(* Logix 5000 project; controller PDPMV1_120_v15 vendor 1 type 14 code 65 rev 15.1; software revision 15.00; part 2 of 3 *)
(* tags used below, declared in another part *)
   MVI69PDPMV1 : PDPMV1_ModuleDef;
(* MainProgram, continued *)

ROUTINE MainRoutine   (* ladder *)
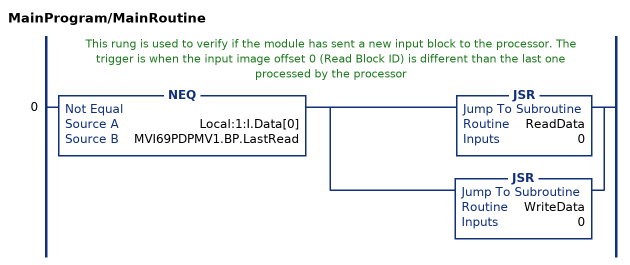
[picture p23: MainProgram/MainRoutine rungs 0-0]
   // This rung is used to verify if the module has sent a new input block to the processor. The trigger is when the input image offset 0 (Read Block ID) is different than the last one processed by the processor
   0: NEQ(Local:1:I.Data[0],MVI69PDPMV1.BP.LastRead)[JSR(ReadData,0) ,JSR(WriteData,0) ];
END_ROUTINE

ROUTINE ReadAlarm   (* ladder *)
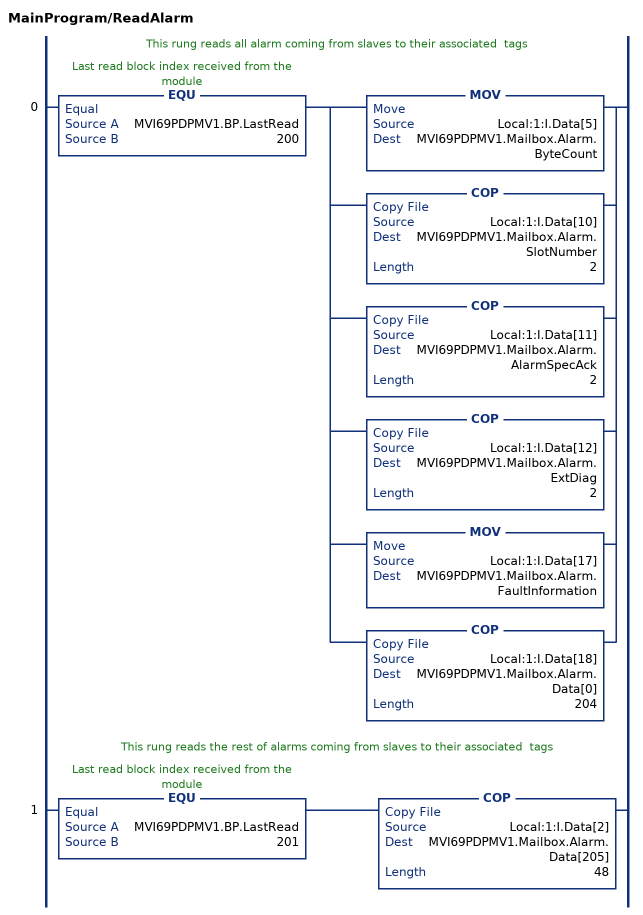
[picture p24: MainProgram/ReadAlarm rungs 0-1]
   // This rung reads all alarm coming from slaves to their associated  tags
   0: EQU(MVI69PDPMV1.BP.LastRead,200)[MOV(Local:1:I.Data[5],MVI69PDPMV1.Mailbox.Alarm.ByteCount) ,COP(Local:1:I.Data[10],MVI69PDPMV1.Mailbox.Alarm.SlotNumber,2) ,COP(Local:1:I.Data[11],MVI69PDPMV1.Mailbox.Alarm.AlarmSpecAck,2) ,COP(Local:1:I.Data[12],MVI69PDPMV1.Mailbox.Alarm.ExtDiag,2) ,MOV(Local:1:I.Data[17],MVI69PDPMV1.Mailbox.Alarm.FaultInformation) ,COP(Local:1:I.Data[18],MVI69PDPMV1.Mailbox.Alarm.Data[0],204) ];
   // This rung reads the rest of alarms coming from slaves to their associated  tags
   1: EQU(MVI69PDPMV1.BP.LastRead,201)COP(Local:1:I.Data[2],MVI69PDPMV1.Mailbox.Alarm.Data[205],48);
END_ROUTINE

ROUTINE ReadData   (* ladder *)
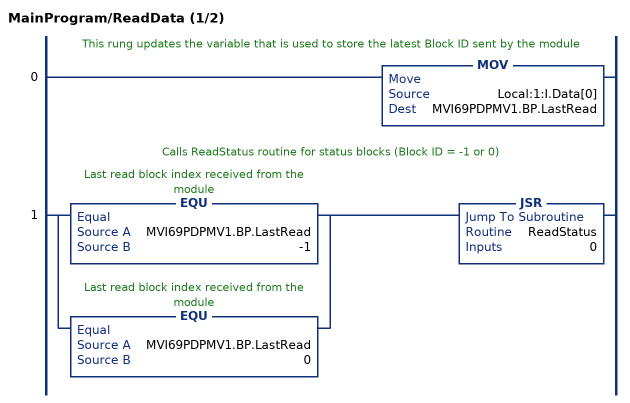
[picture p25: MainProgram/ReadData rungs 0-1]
   // This rung updates the variable that is used to store the latest Block ID sent by the module
   0: MOV(Local:1:I.Data[0],MVI69PDPMV1.BP.LastRead);
   // Calls ReadStatus routine for status blocks (Block ID = -1 or 0)
   1: [EQU(MVI69PDPMV1.BP.LastRead,-1) ,EQU(MVI69PDPMV1.BP.LastRead,0) ]JSR(ReadStatus,0);
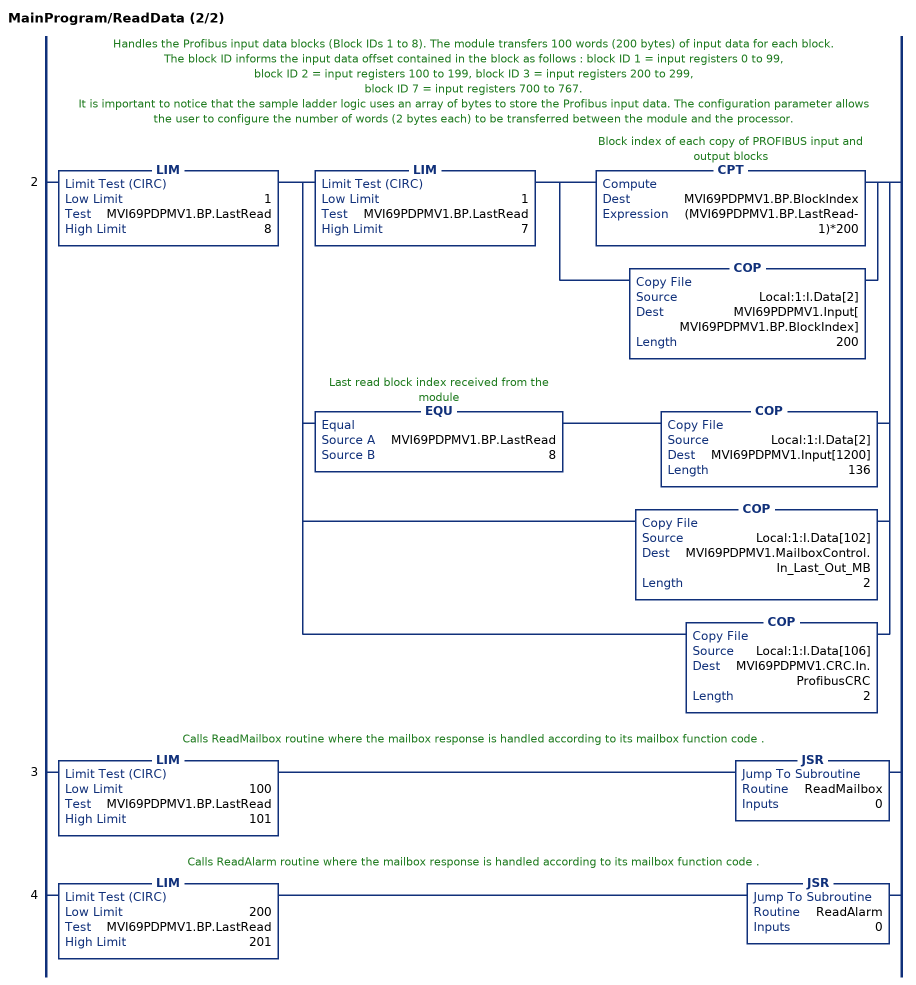
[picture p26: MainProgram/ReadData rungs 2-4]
   // Handles the Profibus input data blocks (Block IDs 1 to 8). The module transfers 100 words (200 bytes) of input data for each block.
   // The block ID informs the input data offset contained in the block as follows : block ID 1 = input registers 0 to 99,
   // block ID 2 = input registers 100 to 199, block ID 3 = input registers 200 to 299,
   // block ID 7 = input registers 700 to 767.
   // It is important to notice that the sample ladder logic uses an array of bytes to store the Profibus input data. The configuration parameter allows the user to configure the number of words (2 bytes each) to be transferred between the module and the processor.
   2: LIM(1,MVI69PDPMV1.BP.LastRead,8)[LIM(1,MVI69PDPMV1.BP.LastRead,7) [CPT(MVI69PDPMV1.BP.BlockIndex,(MVI69PDPMV1.BP.LastRead-1)*200) ,COP(Local:1:I.Data[2],MVI69PDPMV1.Input[MVI69PDPMV1.BP.BlockIndex],200) ] ,EQU(MVI69PDPMV1.BP.LastRead,8) COP(Local:1:I.Data[2],MVI69PDPMV1.Input[1200],136) ,COP(Local:1:I.Data[102],MVI69PDPMV1.MailboxControl.In_Last_Out_MB,2) ,COP(Local:1:I.Data[106],MVI69PDPMV1.CRC.In.ProfibusCRC,2) ];
   // Calls ReadMailbox routine where the mailbox response is handled according to its mailbox function code .
   3: LIM(100,MVI69PDPMV1.BP.LastRead,101)JSR(ReadMailbox,0);
   // Calls ReadAlarm routine where the mailbox response is handled according to its mailbox function code .
   4: LIM(200,MVI69PDPMV1.BP.LastRead,201)JSR(ReadAlarm,0);
END_ROUTINE

ROUTINE ReadMailbox   (* ladder *)
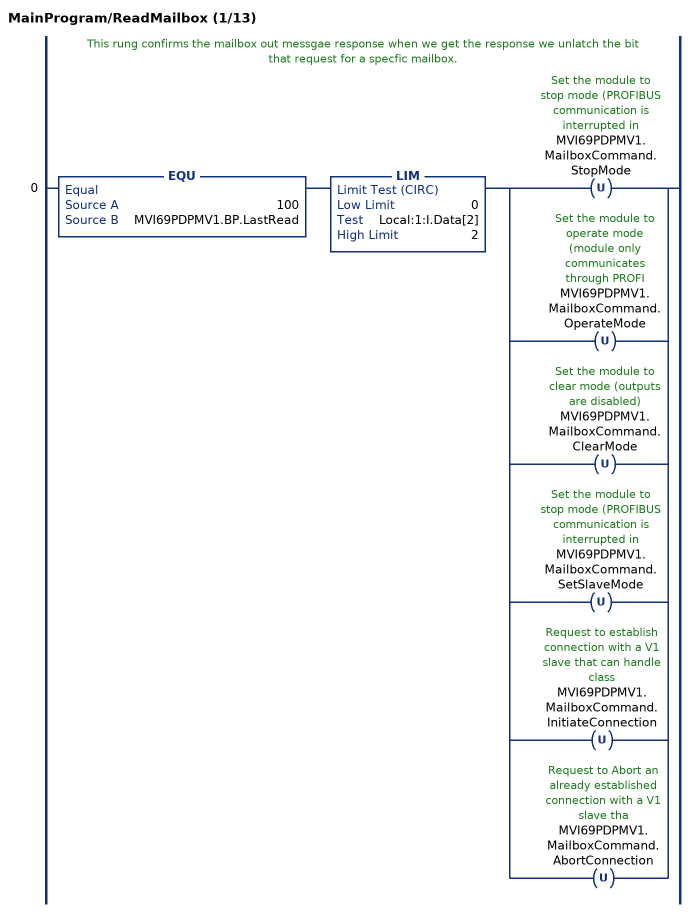
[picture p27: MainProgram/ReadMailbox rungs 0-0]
   // This rung confirms the mailbox out messgae response when we get the response we unlatch the bit that request for a specfic mailbox.
   0: EQU(100,MVI69PDPMV1.BP.LastRead)LIM(0,Local:1:I.Data[2],2)[OTU(MVI69PDPMV1.MailboxCommand.StopMode) ,OTU(MVI69PDPMV1.MailboxCommand.OperateMode) ,OTU(MVI69PDPMV1.MailboxCommand.ClearMode) ,OTU(MVI69PDPMV1.MailboxCommand.SetSlaveMode) ,OTU(MVI69PDPMV1.MailboxCommand.InitiateConnection) ,OTU(MVI69PDPMV1.MailboxCommand.AbortConnection) ];
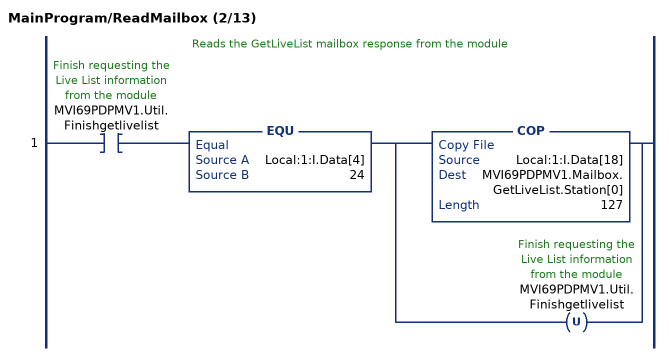
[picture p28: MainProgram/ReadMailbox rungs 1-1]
   // Reads the GetLiveList mailbox response from the module
   1: XIC(MVI69PDPMV1.Util.Finishgetlivelist)EQU(Local:1:I.Data[4],24)[COP(Local:1:I.Data[18],MVI69PDPMV1.Mailbox.GetLiveList.Station[0],127) ,OTU(MVI69PDPMV1.Util.Finishgetlivelist) ];
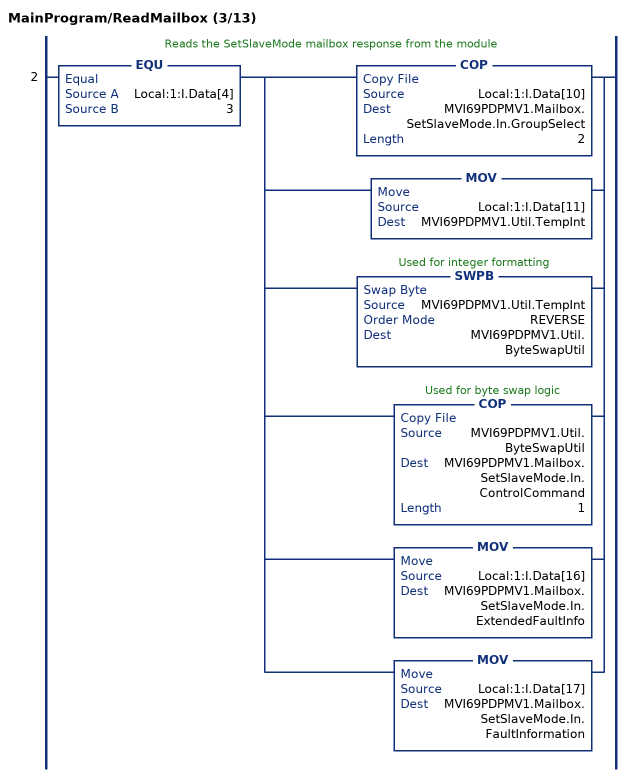
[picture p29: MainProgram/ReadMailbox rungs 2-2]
   // Reads the SetSlaveMode mailbox response from the module
   2: EQU(Local:1:I.Data[4],3)[COP(Local:1:I.Data[10],MVI69PDPMV1.Mailbox.SetSlaveMode.In.GroupSelect,2) ,MOV(Local:1:I.Data[11],MVI69PDPMV1.Util.TempInt) ,SWPB(MVI69PDPMV1.Util.TempInt,REVERSE,MVI69PDPMV1.Util.ByteSwapUtil) ,COP(MVI69PDPMV1.Util.ByteSwapUtil,MVI69PDPMV1.Mailbox.SetSlaveMode.In.ControlCommand,1) ,MOV(Local:1:I.Data[16],MVI69PDPMV1.Mailbox.SetSlaveMode.In.ExtendedFaultInfo) ,MOV(Local:1:I.Data[17],MVI69PDPMV1.Mailbox.SetSlaveMode.In.FaultInformation) ];
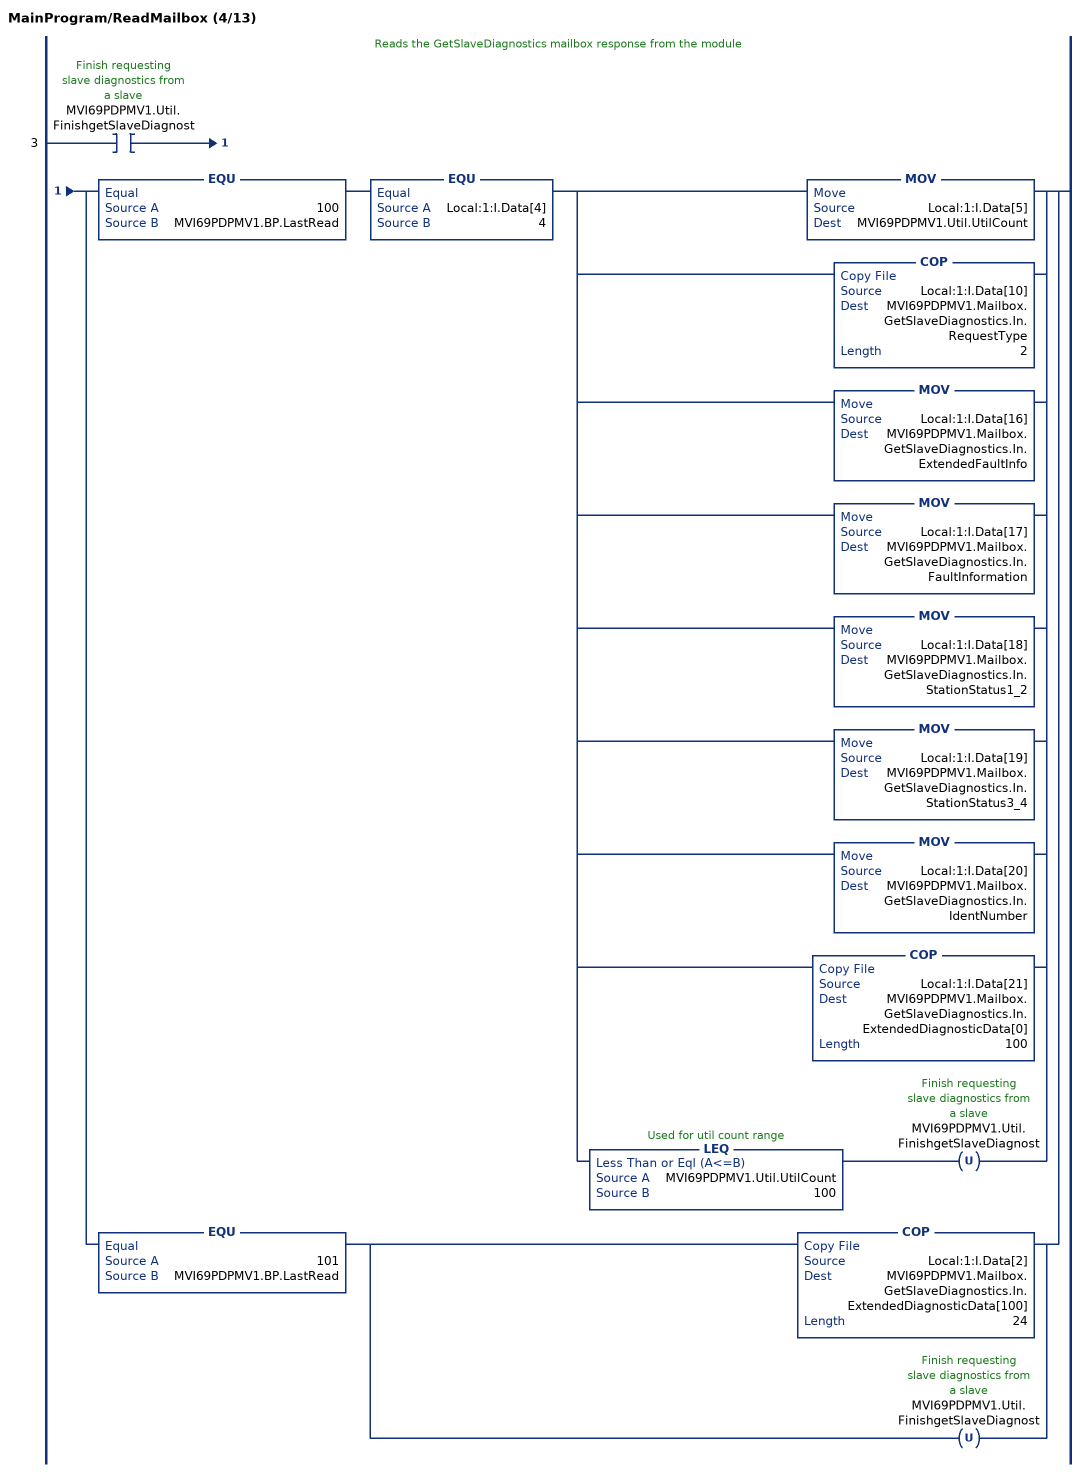
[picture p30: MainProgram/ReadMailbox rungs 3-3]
   // Reads the GetSlaveDiagnostics mailbox response from the module
   3: XIC(MVI69PDPMV1.Util.FinishgetSlaveDiagnost)[EQU(100,MVI69PDPMV1.BP.LastRead) EQU(Local:1:I.Data[4],4) [MOV(Local:1:I.Data[5],MVI69PDPMV1.Util.UtilCount) ,COP(Local:1:I.Data[10],MVI69PDPMV1.Mailbox.GetSlaveDiagnostics.In.RequestType,2) ,MOV(Local:1:I.Data[16],MVI69PDPMV1.Mailbox.GetSlaveDiagnostics.In.ExtendedFaultInfo) ,MOV(Local:1:I.Data[17],MVI69PDPMV1.Mailbox.GetSlaveDiagnostics.In.FaultInformation) ,MOV(Local:1:I.Data[18],MVI69PDPMV1.Mailbox.GetSlaveDiagnostics.In.StationStatus1_2) ,MOV(Local:1:I.Data[19],MVI69PDPMV1.Mailbox.GetSlaveDiagnostics.In.StationStatus3_4) ,MOV(Local:1:I.Data[20],MVI69PDPMV1.Mailbox.GetSlaveDiagnostics.In.IdentNumber) ,COP(Local:1:I.Data[21],MVI69PDPMV1.Mailbox.GetSlaveDiagnostics.In.ExtendedDiagnosticData[0],100) ,LEQ(MVI69PDPMV1.Util.UtilCount,100) OTU(MVI69PDPMV1.Util.FinishgetSlaveDiagnost) ] ,EQU(101,MVI69PDPMV1.BP.LastRead) [COP(Local:1:I.Data[2],MVI69PDPMV1.Mailbox.GetSlaveDiagnostics.In.ExtendedDiagnosticData[100],24) ,OTU(MVI69PDPMV1.Util.FinishgetSlaveDiagnost) ] ];
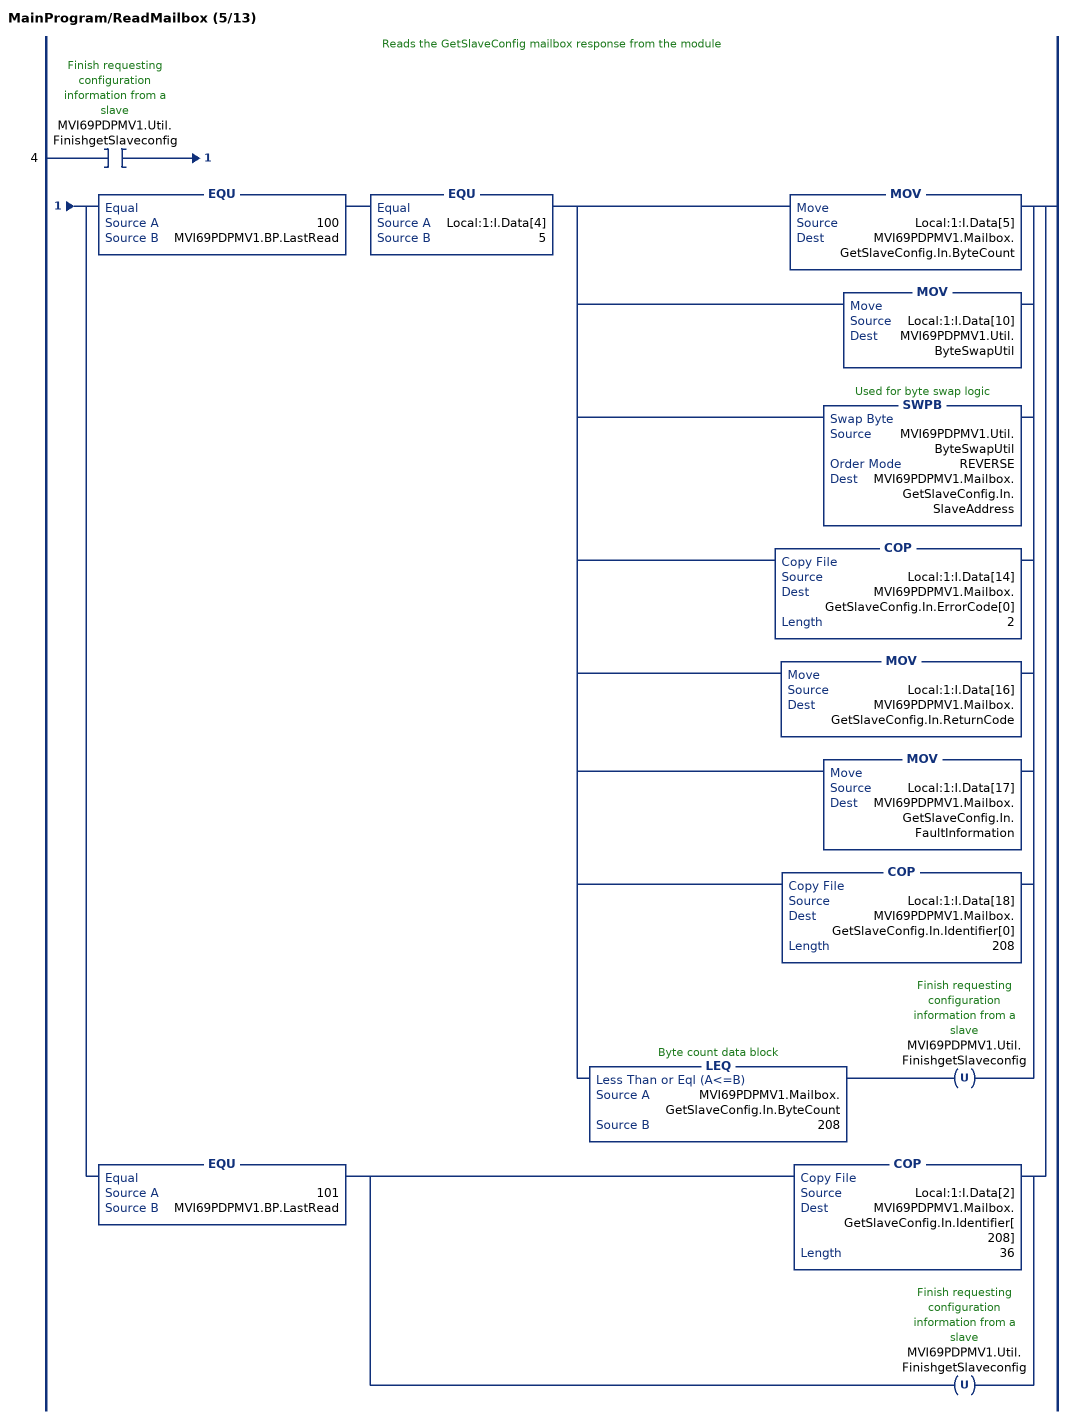
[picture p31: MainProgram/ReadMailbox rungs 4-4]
   // Reads the GetSlaveConfig mailbox response from the module
   4: XIC(MVI69PDPMV1.Util.FinishgetSlaveconfig)[EQU(100,MVI69PDPMV1.BP.LastRead) EQU(Local:1:I.Data[4],5) [MOV(Local:1:I.Data[5],MVI69PDPMV1.Mailbox.GetSlaveConfig.In.ByteCount) ,MOV(Local:1:I.Data[10],MVI69PDPMV1.Util.ByteSwapUtil) ,SWPB(MVI69PDPMV1.Util.ByteSwapUtil,REVERSE,MVI69PDPMV1.Mailbox.GetSlaveConfig.In.SlaveAddress) ,COP(Local:1:I.Data[14],MVI69PDPMV1.Mailbox.GetSlaveConfig.In.ErrorCode[0],2) ,MOV(Local:1:I.Data[16],MVI69PDPMV1.Mailbox.GetSlaveConfig.In.ReturnCode) ,MOV(Local:1:I.Data[17],MVI69PDPMV1.Mailbox.GetSlaveConfig.In.FaultInformation) ,COP(Local:1:I.Data[18],MVI69PDPMV1.Mailbox.GetSlaveConfig.In.Identifier[0],208) ,LEQ(MVI69PDPMV1.Mailbox.GetSlaveConfig.In.ByteCount,208) OTU(MVI69PDPMV1.Util.FinishgetSlaveconfig) ] ,EQU(101,MVI69PDPMV1.BP.LastRead) [COP(Local:1:I.Data[2],MVI69PDPMV1.Mailbox.GetSlaveConfig.In.Identifier[208],36) ,OTU(MVI69PDPMV1.Util.FinishgetSlaveconfig) ] ];
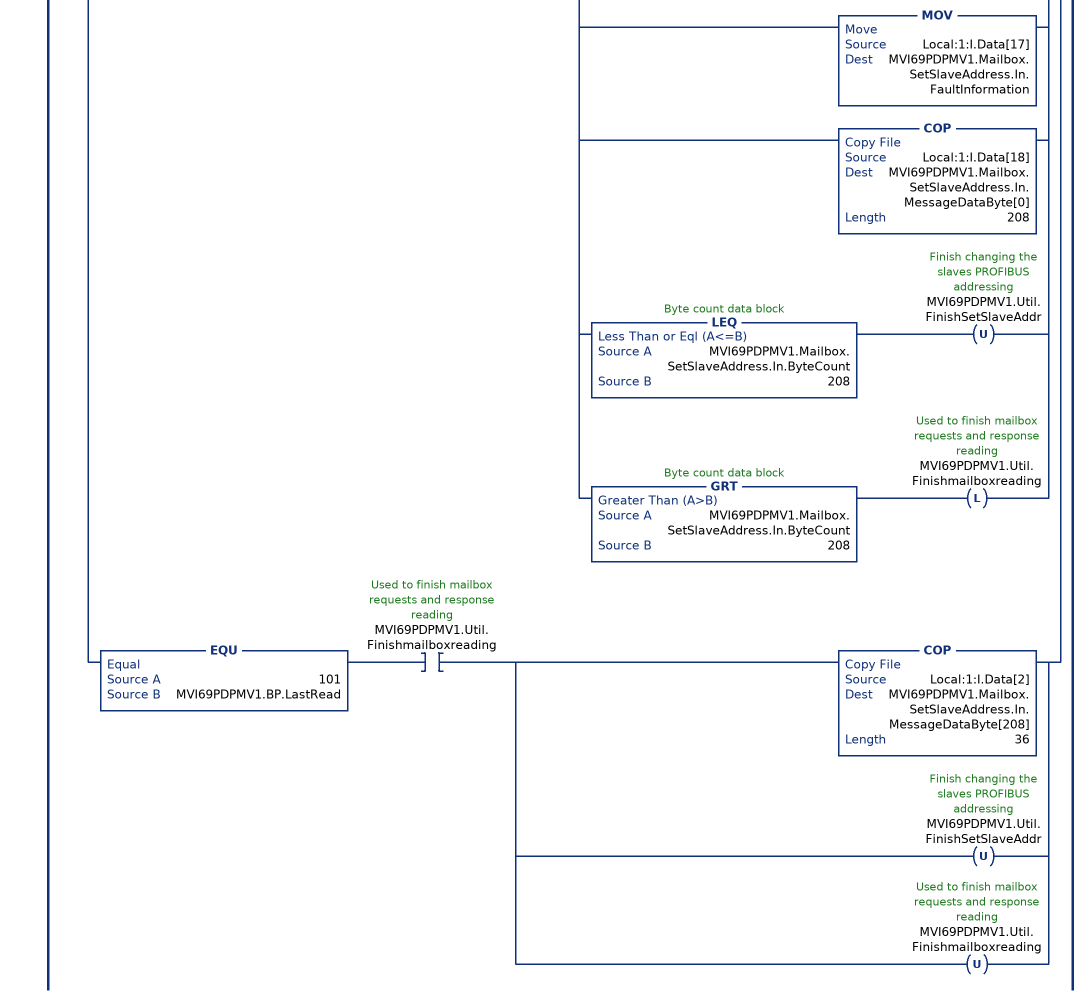
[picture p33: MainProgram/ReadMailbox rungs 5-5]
   // Reads the SetSlaveAddress mailbox response from the module
   5: XIC(MVI69PDPMV1.Util.FinishSetSlaveAddr)[EQU(100,MVI69PDPMV1.BP.LastRead) EQU(Local:1:I.Data[4],6) [MOV(Local:1:I.Data[5],MVI69PDPMV1.Mailbox.SetSlaveAddress.In.ByteCount) ,COP(Local:1:I.Data[10],MVI69PDPMV1.Mailbox.SetSlaveAddress.In.NewSlaveAddress,2) ,MOV(Local:1:I.Data[11],MVI69PDPMV1.Mailbox.SetSlaveAddress.In.SlaveIdentNumber) ,MOV(Local:1:I.Data[12],MVI69PDPMV1.Util.ByteSwapUtil) ,SWPB(MVI69PDPMV1.Util.ByteSwapUtil,REVERSE,MVI69PDPMV1.Mailbox.SetSlaveAddress.In.No_add_Chg) ,MOV(Local:1:I.Data[14],MVI69PDPMV1.Mailbox.SetSlaveAddress.In.ErrorCode1_2) ,MOV(Local:1:I.Data[15],MVI69PDPMV1.Mailbox.SetSlaveAddress.In.ErrorCode3_4) ,MOV(Local:1:I.Data[16],MVI69PDPMV1.Mailbox.SetSlaveAddress.In.ReturnCode) ,MOV(Local:1:I.Data[17],MVI69PDPMV1.Mailbox.SetSlaveAddress.In.FaultInformation) ,COP(Local:1:I.Data[18],MVI69PDPMV1.Mailbox.SetSlaveAddress.In.MessageDataByte[0],208) ,LEQ(MVI69PDPMV1.Mailbox.SetSlaveAddress.In.ByteCount,208) OTU(MVI69PDPMV1.Util.FinishSetSlaveAddr) ,GRT(MVI69PDPMV1.Mailbox.SetSlaveAddress.In.ByteCount,208) OTL(MVI69PDPMV1.Util.Finishmailboxreading) ] ,EQU(101,MVI69PDPMV1.BP.LastRead) XIC(MVI69PDPMV1.Util.Finishmailboxreading) [COP(Local:1:I.Data[2],MVI69PDPMV1.Mailbox.SetSlaveAddress.In.MessageDataByte[208],36) ,OTU(MVI69PDPMV1.Util.FinishSetSlaveAddr) ,OTU(MVI69PDPMV1.Util.Finishmailboxreading) ] ];
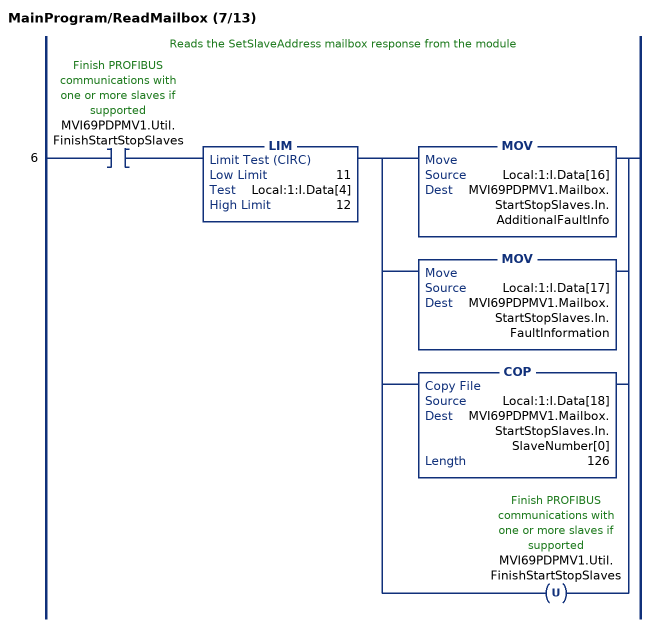
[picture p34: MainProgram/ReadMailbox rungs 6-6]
   // Reads the SetSlaveAddress mailbox response from the module
   6: XIC(MVI69PDPMV1.Util.FinishStartStopSlaves)LIM(11,Local:1:I.Data[4],12)[MOV(Local:1:I.Data[16],MVI69PDPMV1.Mailbox.StartStopSlaves.In.AdditionalFaultInfo) ,MOV(Local:1:I.Data[17],MVI69PDPMV1.Mailbox.StartStopSlaves.In.FaultInformation) ,COP(Local:1:I.Data[18],MVI69PDPMV1.Mailbox.StartStopSlaves.In.SlaveNumber[0],126) ,OTU(MVI69PDPMV1.Util.FinishStartStopSlaves) ];
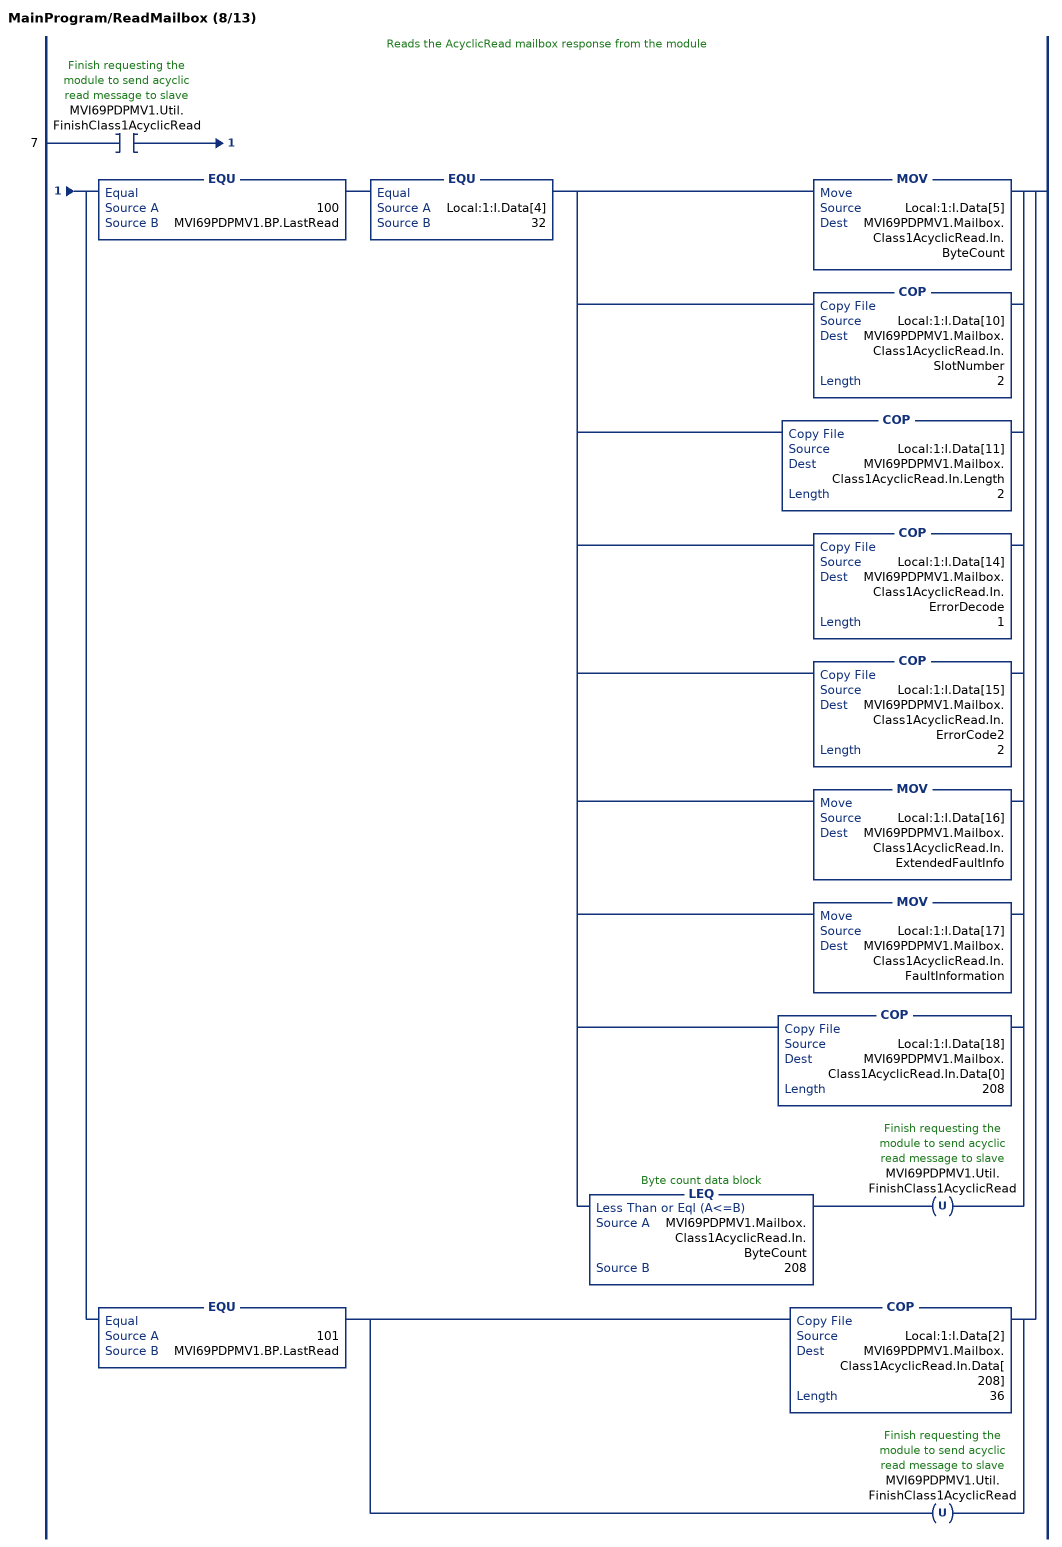
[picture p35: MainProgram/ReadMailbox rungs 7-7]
   // Reads the AcyclicRead mailbox response from the module
   7: XIC(MVI69PDPMV1.Util.FinishClass1AcyclicRead)[EQU(100,MVI69PDPMV1.BP.LastRead) EQU(Local:1:I.Data[4],32) [MOV(Local:1:I.Data[5],MVI69PDPMV1.Mailbox.Class1AcyclicRead.In.ByteCount) ,COP(Local:1:I.Data[10],MVI69PDPMV1.Mailbox.Class1AcyclicRead.In.SlotNumber,2) ,COP(Local:1:I.Data[11],MVI69PDPMV1.Mailbox.Class1AcyclicRead.In.Length,2) ,COP(Local:1:I.Data[14],MVI69PDPMV1.Mailbox.Class1AcyclicRead.In.ErrorDecode,1) ,COP(Local:1:I.Data[15],MVI69PDPMV1.Mailbox.Class1AcyclicRead.In.ErrorCode2,2) ,MOV(Local:1:I.Data[16],MVI69PDPMV1.Mailbox.Class1AcyclicRead.In.ExtendedFaultInfo) ,MOV(Local:1:I.Data[17],MVI69PDPMV1.Mailbox.Class1AcyclicRead.In.FaultInformation) ,COP(Local:1:I.Data[18],MVI69PDPMV1.Mailbox.Class1AcyclicRead.In.Data[0],208) ,LEQ(MVI69PDPMV1.Mailbox.Class1AcyclicRead.In.ByteCount,208) OTU(MVI69PDPMV1.Util.FinishClass1AcyclicRead) ] ,EQU(101,MVI69PDPMV1.BP.LastRead) [COP(Local:1:I.Data[2],MVI69PDPMV1.Mailbox.Class1AcyclicRead.In.Data[208],36) ,OTU(MVI69PDPMV1.Util.FinishClass1AcyclicRead) ] ];
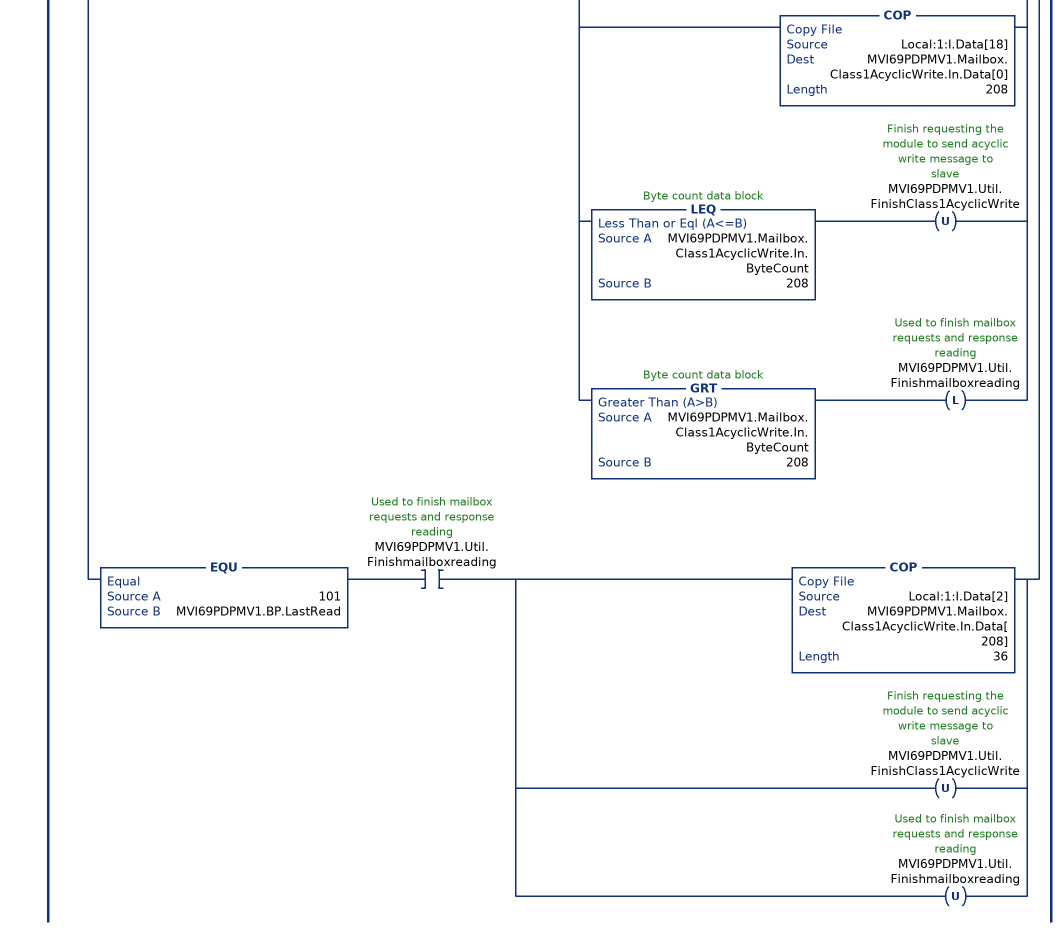
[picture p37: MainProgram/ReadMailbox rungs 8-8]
   // Reads the AcyclicWrite mailbox response from the module
   8: XIC(MVI69PDPMV1.Util.FinishClass1AcyclicWrite)[EQU(Local:1:I.Data[4],33) EQU(100,MVI69PDPMV1.BP.LastRead) [MOV(Local:1:I.Data[5],MVI69PDPMV1.Mailbox.Class1AcyclicWrite.In.ByteCount) ,COP(Local:1:I.Data[10],MVI69PDPMV1.Mailbox.Class1AcyclicWrite.In.SlotNumber,2) ,COP(Local:1:I.Data[11],MVI69PDPMV1.Mailbox.Class1AcyclicWrite.In.Length,2) ,COP(Local:1:I.Data[14],MVI69PDPMV1.Mailbox.Class1AcyclicWrite.In.ErrorDecode,1) ,COP(Local:1:I.Data[15],MVI69PDPMV1.Mailbox.Class1AcyclicWrite.In.ErrorCode2,2) ,MOV(Local:1:I.Data[16],MVI69PDPMV1.Mailbox.Class1AcyclicWrite.In.ExtendedFaultInfo) ,MOV(Local:1:I.Data[17],MVI69PDPMV1.Mailbox.Class1AcyclicWrite.In.FaultInformation) ,COP(Local:1:I.Data[18],MVI69PDPMV1.Mailbox.Class1AcyclicWrite.In.Data[0],208) ,LEQ(MVI69PDPMV1.Mailbox.Class1AcyclicWrite.In.ByteCount,208) OTU(MVI69PDPMV1.Util.FinishClass1AcyclicWrite) ,GRT(MVI69PDPMV1.Mailbox.Class1AcyclicWrite.In.ByteCount,208) OTL(MVI69PDPMV1.Util.Finishmailboxreading) ] ,EQU(101,MVI69PDPMV1.BP.LastRead) XIC(MVI69PDPMV1.Util.Finishmailboxreading) [COP(Local:1:I.Data[2],MVI69PDPMV1.Mailbox.Class1AcyclicWrite.In.Data[208],36) ,OTU(MVI69PDPMV1.Util.FinishClass1AcyclicWrite) ,OTU(MVI69PDPMV1.Util.Finishmailboxreading) ] ];
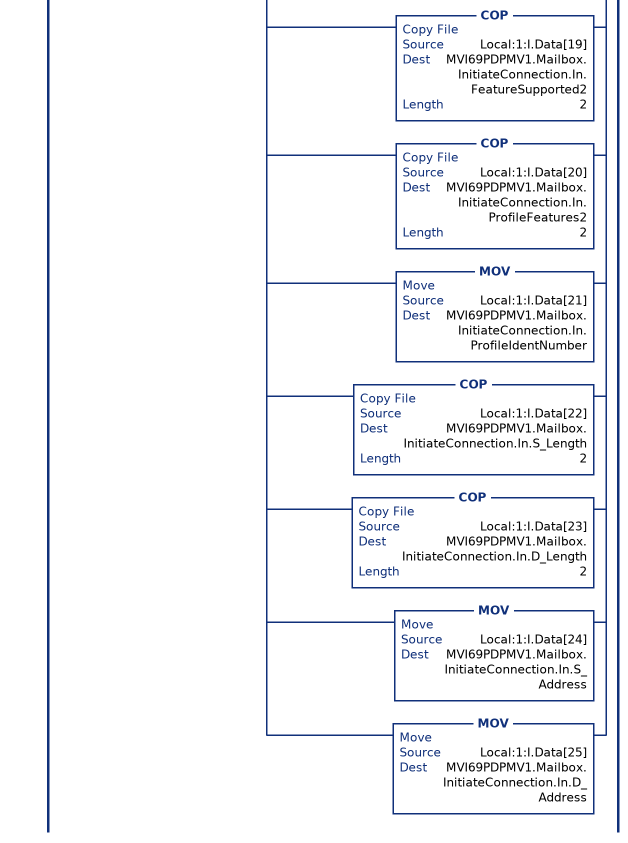
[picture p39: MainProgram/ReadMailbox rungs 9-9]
   // Reads the Initiate connection mailbox response from the module
   9: EQU(Local:1:I.Data[4],37)[MOV(Local:1:I.Data[5],MVI69PDPMV1.Mailbox.InitiateConnection.In.SizeofdatainBytes) ,MOV(Local:1:I.Data[10],MVI69PDPMV1.Mailbox.InitiateConnection.In.C_REF) ,COP(Local:1:I.Data[11],MVI69PDPMV1.Mailbox.InitiateConnection.In.MaxDataLength,2) ,MOV(Local:1:I.Data[12],MVI69PDPMV1.Mailbox.InitiateConnection.In.MinmumSlaveTimeout) ,COP(Local:1:I.Data[14],MVI69PDPMV1.Mailbox.InitiateConnection.In.ErrorDecode,1) ,COP(Local:1:I.Data[15],MVI69PDPMV1.Mailbox.InitiateConnection.In.ErrorCode2,2) ,MOV(Local:1:I.Data[16],MVI69PDPMV1.Mailbox.InitiateConnection.In.ExtendedFaultInformation) ,MOV(Local:1:I.Data[17],MVI69PDPMV1.Mailbox.InitiateConnection.In.FaultInformation) ,MOV(Local:1:I.Data[18],MVI69PDPMV1.Mailbox.InitiateConnection.In.SendTimeout) ,COP(Local:1:I.Data[19],MVI69PDPMV1.Mailbox.InitiateConnection.In.FeatureSupported2,2) ,COP(Local:1:I.Data[20],MVI69PDPMV1.Mailbox.InitiateConnection.In.ProfileFeatures2,2) ,MOV(Local:1:I.Data[21],MVI69PDPMV1.Mailbox.InitiateConnection.In.ProfileIdentNumber) ,COP(Local:1:I.Data[22],MVI69PDPMV1.Mailbox.InitiateConnection.In.S_Length,2) ,COP(Local:1:I.Data[23],MVI69PDPMV1.Mailbox.InitiateConnection.In.D_Length,2) ,MOV(Local:1:I.Data[24],MVI69PDPMV1.Mailbox.InitiateConnection.In.S_Address) ,MOV(Local:1:I.Data[25],MVI69PDPMV1.Mailbox.InitiateConnection.In.D_Address) ];
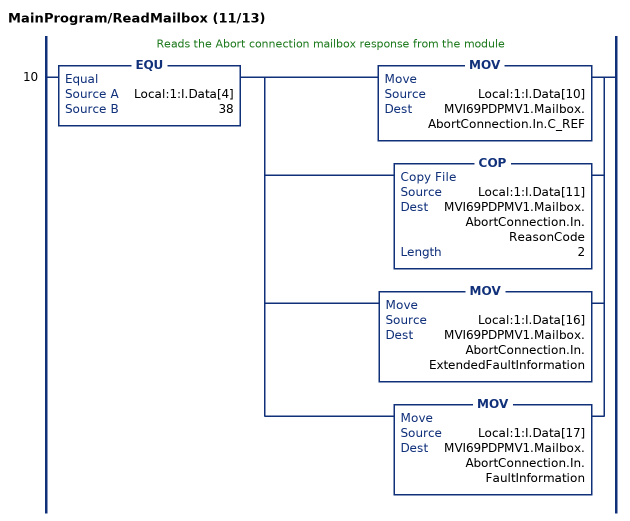
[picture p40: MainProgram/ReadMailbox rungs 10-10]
   // Reads the Abort connection mailbox response from the module
   10: EQU(Local:1:I.Data[4],38)[MOV(Local:1:I.Data[10],MVI69PDPMV1.Mailbox.AbortConnection.In.C_REF) ,COP(Local:1:I.Data[11],MVI69PDPMV1.Mailbox.AbortConnection.In.ReasonCode,2) ,MOV(Local:1:I.Data[16],MVI69PDPMV1.Mailbox.AbortConnection.In.ExtendedFaultInformation) ,MOV(Local:1:I.Data[17],MVI69PDPMV1.Mailbox.AbortConnection.In.FaultInformation) ];
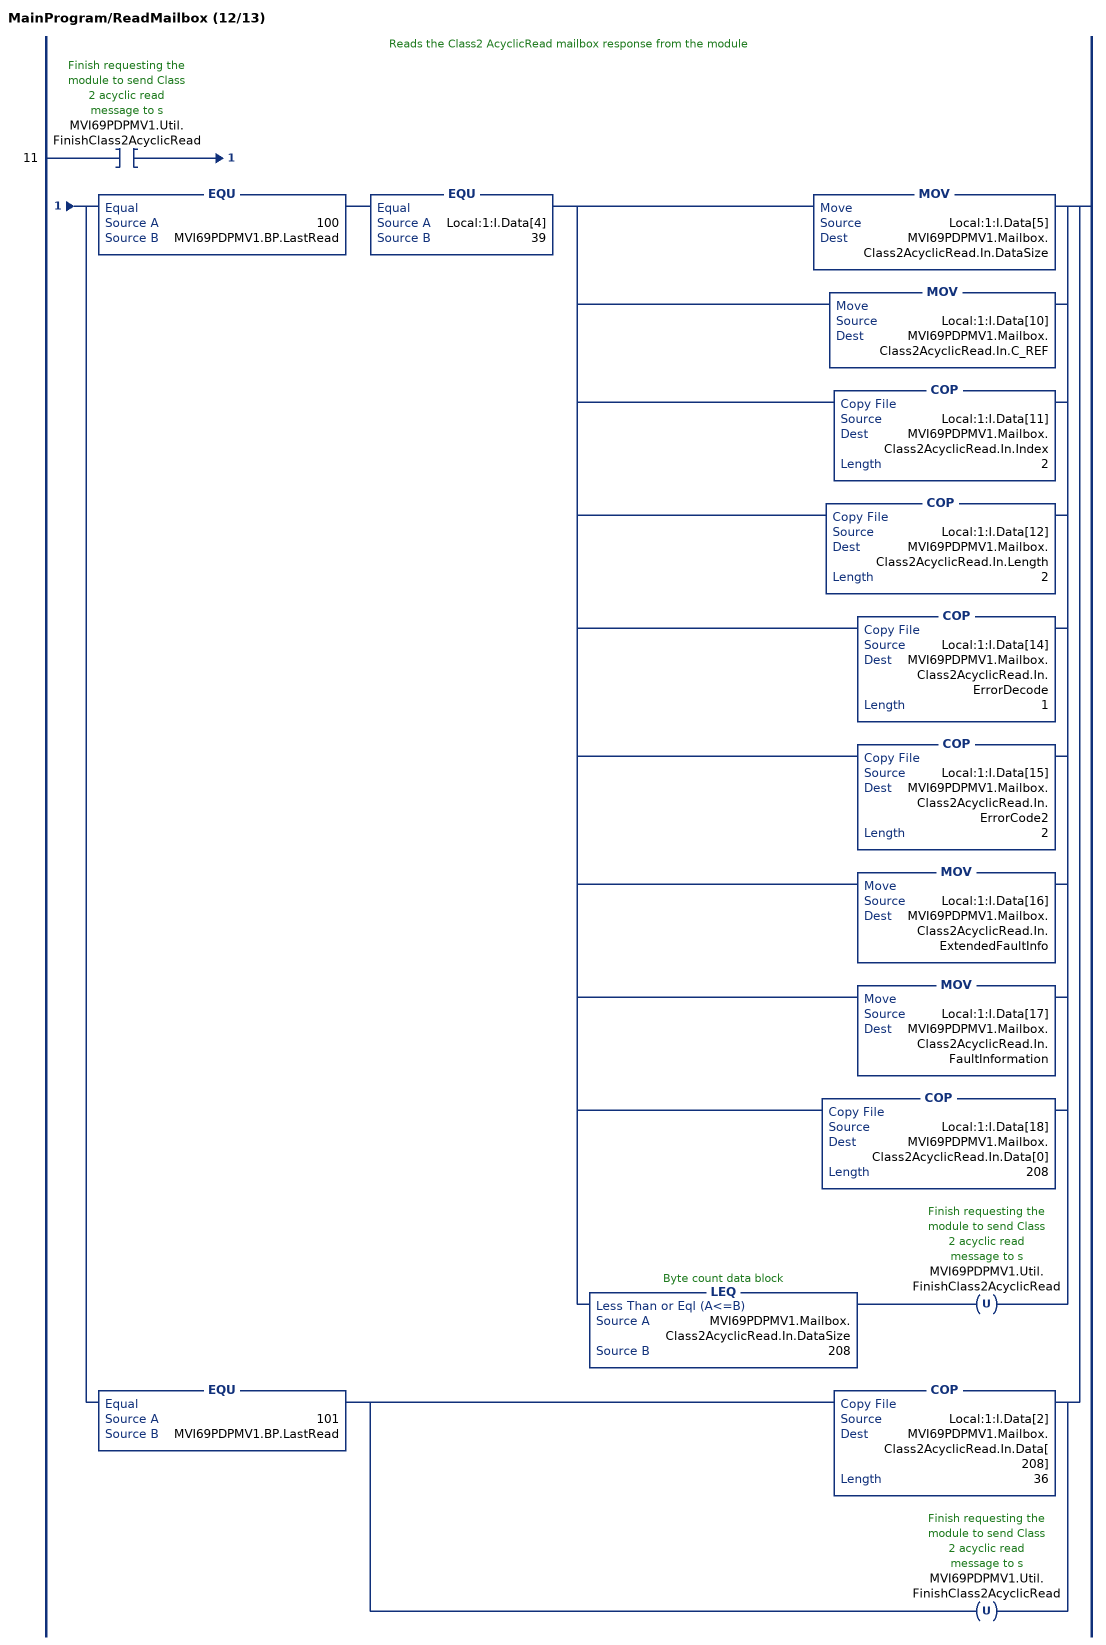
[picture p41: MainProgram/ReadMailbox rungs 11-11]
   // Reads the Class2 AcyclicRead mailbox response from the module
   11: XIC(MVI69PDPMV1.Util.FinishClass2AcyclicRead)[EQU(100,MVI69PDPMV1.BP.LastRead) EQU(Local:1:I.Data[4],39) [MOV(Local:1:I.Data[5],MVI69PDPMV1.Mailbox.Class2AcyclicRead.In.DataSize) ,MOV(Local:1:I.Data[10],MVI69PDPMV1.Mailbox.Class2AcyclicRead.In.C_REF) ,COP(Local:1:I.Data[11],MVI69PDPMV1.Mailbox.Class2AcyclicRead.In.Index,2) ,COP(Local:1:I.Data[12],MVI69PDPMV1.Mailbox.Class2AcyclicRead.In.Length,2) ,COP(Local:1:I.Data[14],MVI69PDPMV1.Mailbox.Class2AcyclicRead.In.ErrorDecode,1) ,COP(Local:1:I.Data[15],MVI69PDPMV1.Mailbox.Class2AcyclicRead.In.ErrorCode2,2) ,MOV(Local:1:I.Data[16],MVI69PDPMV1.Mailbox.Class2AcyclicRead.In.ExtendedFaultInfo) ,MOV(Local:1:I.Data[17],MVI69PDPMV1.Mailbox.Class2AcyclicRead.In.FaultInformation) ,COP(Local:1:I.Data[18],MVI69PDPMV1.Mailbox.Class2AcyclicRead.In.Data[0],208) ,LEQ(MVI69PDPMV1.Mailbox.Class2AcyclicRead.In.DataSize,208) OTU(MVI69PDPMV1.Util.FinishClass2AcyclicRead) ] ,EQU(101,MVI69PDPMV1.BP.LastRead) [COP(Local:1:I.Data[2],MVI69PDPMV1.Mailbox.Class2AcyclicRead.In.Data[208],36) ,OTU(MVI69PDPMV1.Util.FinishClass2AcyclicRead) ] ];
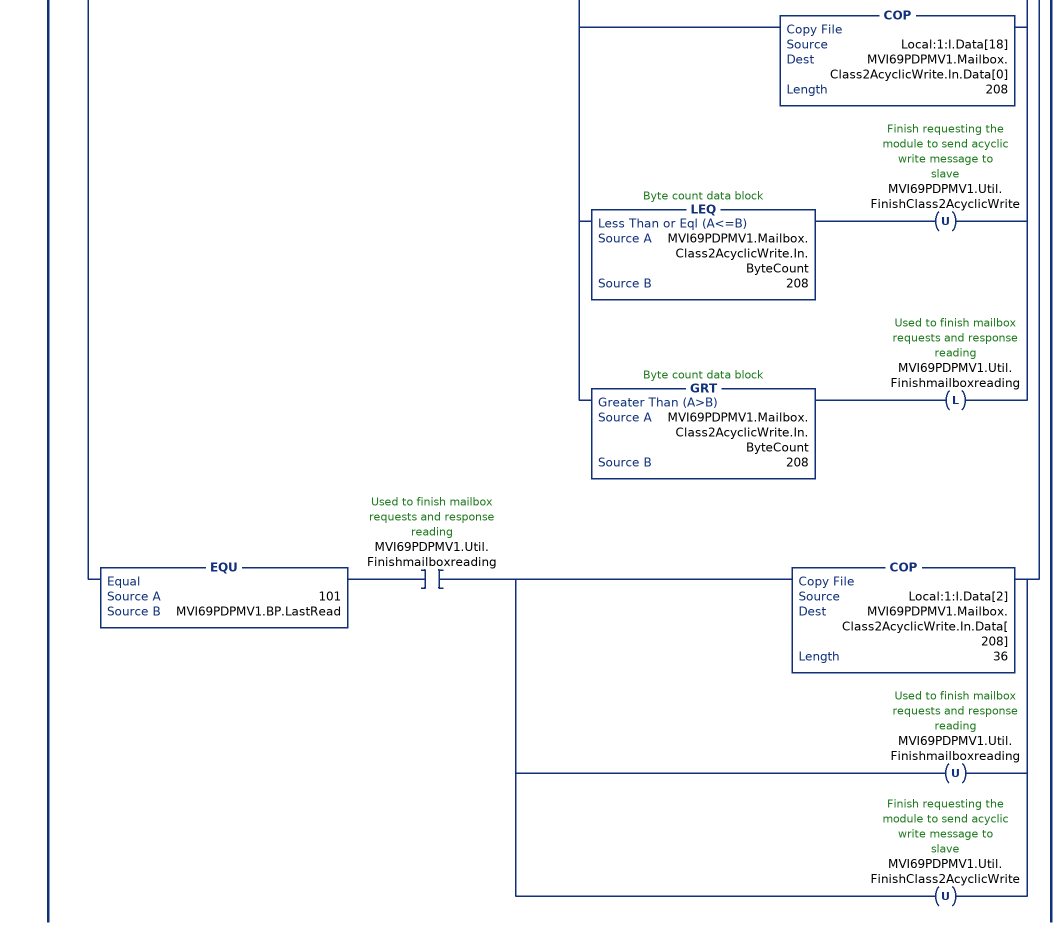
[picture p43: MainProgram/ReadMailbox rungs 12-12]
   // Reads the AcyclicWrite mailbox response from the module
   12: XIC(MVI69PDPMV1.Util.FinishClass2AcyclicWrite)[EQU(100,MVI69PDPMV1.BP.LastRead) EQU(Local:1:I.Data[4],40) [MOV(Local:1:I.Data[5],MVI69PDPMV1.Mailbox.Class2AcyclicWrite.In.ByteCount) ,MOV(Local:1:I.Data[10],MVI69PDPMV1.Mailbox.Class2AcyclicWrite.In.C_REF) ,COP(Local:1:I.Data[11],MVI69PDPMV1.Mailbox.Class2AcyclicWrite.In.Index,2) ,COP(Local:1:I.Data[12],MVI69PDPMV1.Mailbox.Class2AcyclicWrite.In.Length,1) ,COP(Local:1:I.Data[14],MVI69PDPMV1.Mailbox.Class2AcyclicWrite.In.ErrorDecode,1) ,COP(Local:1:I.Data[15],MVI69PDPMV1.Mailbox.Class2AcyclicWrite.In.ErrorCode2,2) ,MOV(Local:1:I.Data[16],MVI69PDPMV1.Mailbox.Class2AcyclicWrite.In.ExtendedFaultInfo) ,MOV(Local:1:I.Data[17],MVI69PDPMV1.Mailbox.Class2AcyclicWrite.In.FaultInformation) ,COP(Local:1:I.Data[18],MVI69PDPMV1.Mailbox.Class2AcyclicWrite.In.Data[0],208) ,LEQ(MVI69PDPMV1.Mailbox.Class2AcyclicWrite.In.ByteCount,208) OTU(MVI69PDPMV1.Util.FinishClass2AcyclicWrite) ,GRT(MVI69PDPMV1.Mailbox.Class2AcyclicWrite.In.ByteCount,208) OTL(MVI69PDPMV1.Util.Finishmailboxreading) ] ,EQU(101,MVI69PDPMV1.BP.LastRead) XIC(MVI69PDPMV1.Util.Finishmailboxreading) [COP(Local:1:I.Data[2],MVI69PDPMV1.Mailbox.Class2AcyclicWrite.In.Data[208],36) ,OTU(MVI69PDPMV1.Util.Finishmailboxreading) ,OTU(MVI69PDPMV1.Util.FinishClass2AcyclicWrite) ] ];
END_ROUTINE

ROUTINE ReadStatus   (* ladder *)
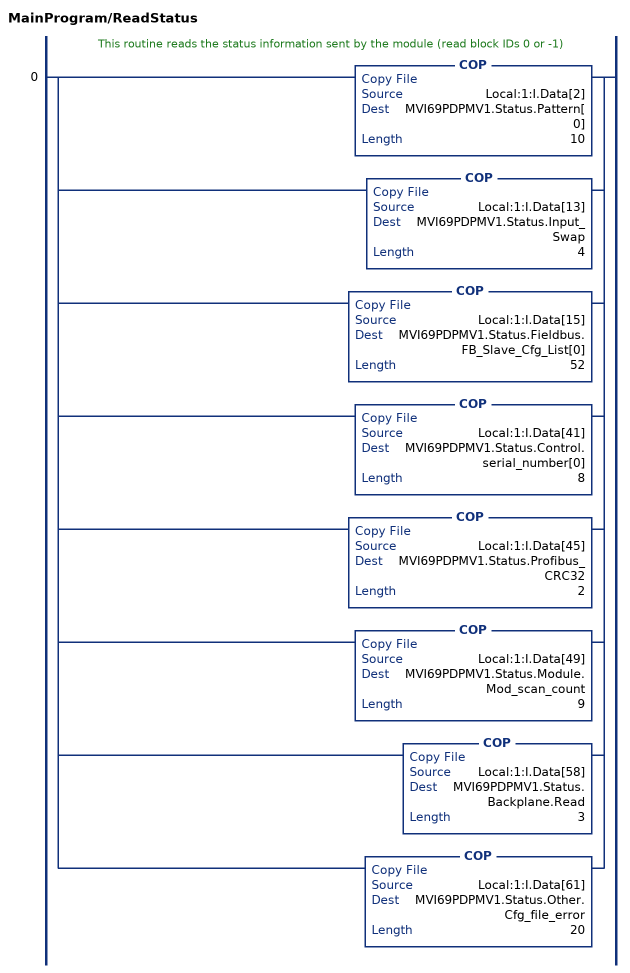
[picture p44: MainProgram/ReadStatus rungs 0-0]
   // This routine reads the status information sent by the module (read block IDs 0 or -1)
   0: [COP(Local:1:I.Data[2],MVI69PDPMV1.Status.Pattern[0],10) ,COP(Local:1:I.Data[13],MVI69PDPMV1.Status.Input_Swap,4) ,COP(Local:1:I.Data[15],MVI69PDPMV1.Status.Fieldbus.FB_Slave_Cfg_List[0],52) ,COP(Local:1:I.Data[41],MVI69PDPMV1.Status.Control.serial_number[0],8) ,COP(Local:1:I.Data[45],MVI69PDPMV1.Status.Profibus_CRC32,2) ,COP(Local:1:I.Data[49],MVI69PDPMV1.Status.Module.Mod_scan_count,9) ,COP(Local:1:I.Data[58],MVI69PDPMV1.Status.Backplane.Read,3) ,COP(Local:1:I.Data[61],MVI69PDPMV1.Status.Other.Cfg_file_error,20) ];
END_ROUTINE
(* Logix 5000 project; controller PDPMV1_120_v15 vendor 1 type 14 code 65 rev 15.1; software revision 15.00; part 3 of 3 *)
(* tags used below, declared in another part *)
   MVI69PDPMV1 : PDPMV1_ModuleDef;
(* MainProgram, continued *)

ROUTINE WriteData   (* ladder *)
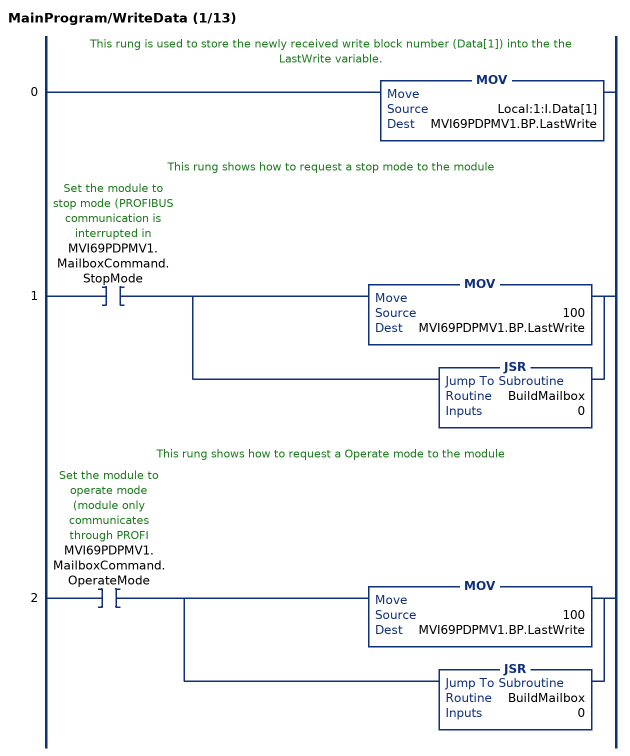
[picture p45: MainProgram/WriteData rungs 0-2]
   // This rung is used to store the newly received write block number (Data[1]) into the the LastWrite variable.
   0: MOV(Local:1:I.Data[1],MVI69PDPMV1.BP.LastWrite);
   // This rung shows how to request a stop mode to the module
   1: XIC(MVI69PDPMV1.MailboxCommand.StopMode)[MOV(100,MVI69PDPMV1.BP.LastWrite) ,JSR(BuildMailbox,0) ];
   // This rung shows how to request a Operate mode to the module
   2: XIC(MVI69PDPMV1.MailboxCommand.OperateMode)[MOV(100,MVI69PDPMV1.BP.LastWrite) ,JSR(BuildMailbox,0) ];
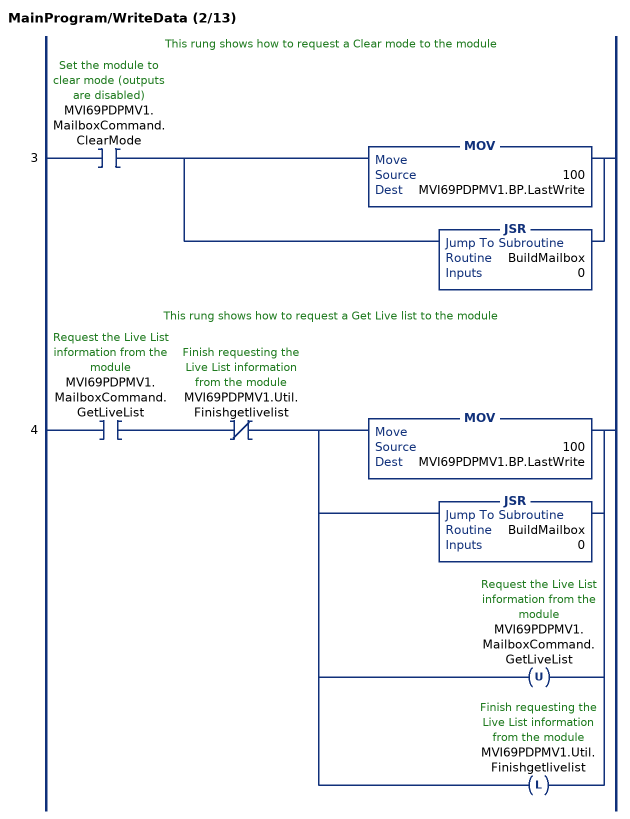
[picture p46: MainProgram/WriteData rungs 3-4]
   // This rung shows how to request a Clear mode to the module
   3: XIC(MVI69PDPMV1.MailboxCommand.ClearMode)[MOV(100,MVI69PDPMV1.BP.LastWrite) ,JSR(BuildMailbox,0) ];
   // This rung shows how to request a Get Live list to the module
   4: XIC(MVI69PDPMV1.MailboxCommand.GetLiveList)XIO(MVI69PDPMV1.Util.Finishgetlivelist)[MOV(100,MVI69PDPMV1.BP.LastWrite) ,JSR(BuildMailbox,0) ,OTU(MVI69PDPMV1.MailboxCommand.GetLiveList) ,OTL(MVI69PDPMV1.Util.Finishgetlivelist) ];
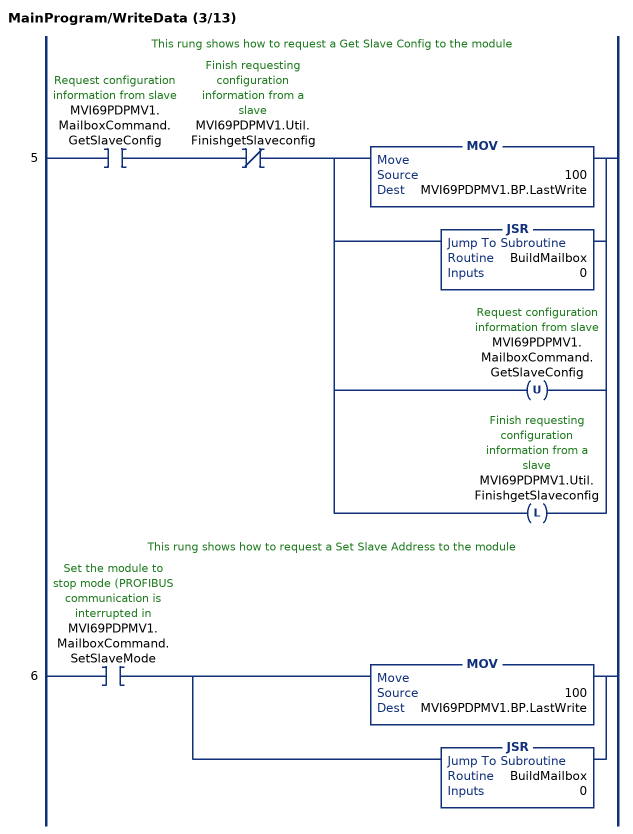
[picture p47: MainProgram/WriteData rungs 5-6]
   // This rung shows how to request a Get Slave Config to the module
   5: XIC(MVI69PDPMV1.MailboxCommand.GetSlaveConfig)XIO(MVI69PDPMV1.Util.FinishgetSlaveconfig)[MOV(100,MVI69PDPMV1.BP.LastWrite) ,JSR(BuildMailbox,0) ,OTU(MVI69PDPMV1.MailboxCommand.GetSlaveConfig) ,OTL(MVI69PDPMV1.Util.FinishgetSlaveconfig) ];
   // This rung shows how to request a Set Slave Address to the module
   6: XIC(MVI69PDPMV1.MailboxCommand.SetSlaveMode)[MOV(100,MVI69PDPMV1.BP.LastWrite) ,JSR(BuildMailbox,0) ];
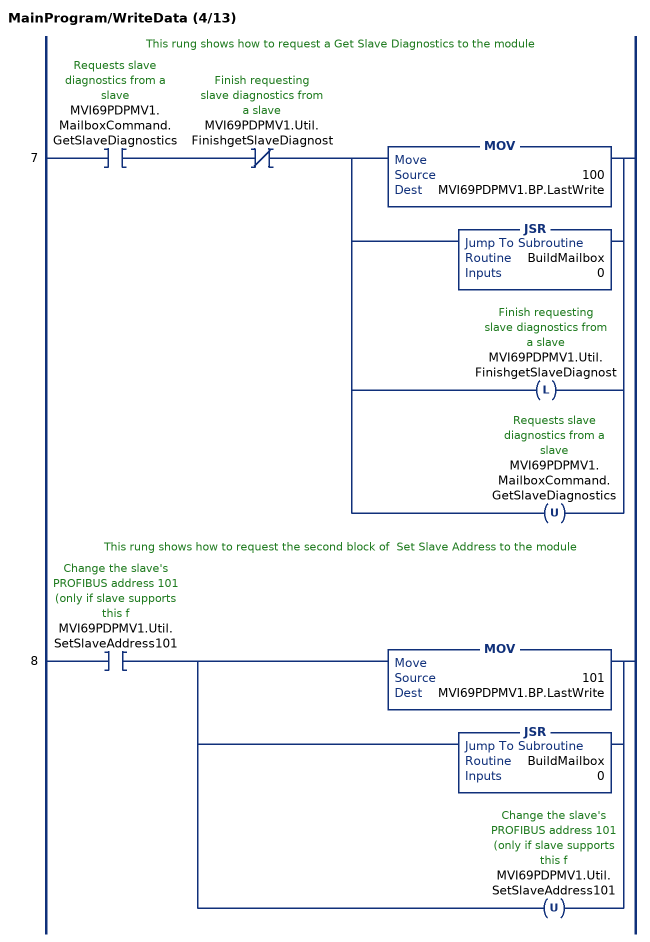
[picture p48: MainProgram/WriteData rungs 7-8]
   // This rung shows how to request a Get Slave Diagnostics to the module
   7: XIC(MVI69PDPMV1.MailboxCommand.GetSlaveDiagnostics)XIO(MVI69PDPMV1.Util.FinishgetSlaveDiagnost)[MOV(100,MVI69PDPMV1.BP.LastWrite) ,JSR(BuildMailbox,0) ,OTL(MVI69PDPMV1.Util.FinishgetSlaveDiagnost) ,OTU(MVI69PDPMV1.MailboxCommand.GetSlaveDiagnostics) ];
   // This rung shows how to request the second block of  Set Slave Address to the module
   8: XIC(MVI69PDPMV1.Util.SetSlaveAddress101)[MOV(101,MVI69PDPMV1.BP.LastWrite) ,JSR(BuildMailbox,0) ,OTU(MVI69PDPMV1.Util.SetSlaveAddress101) ];
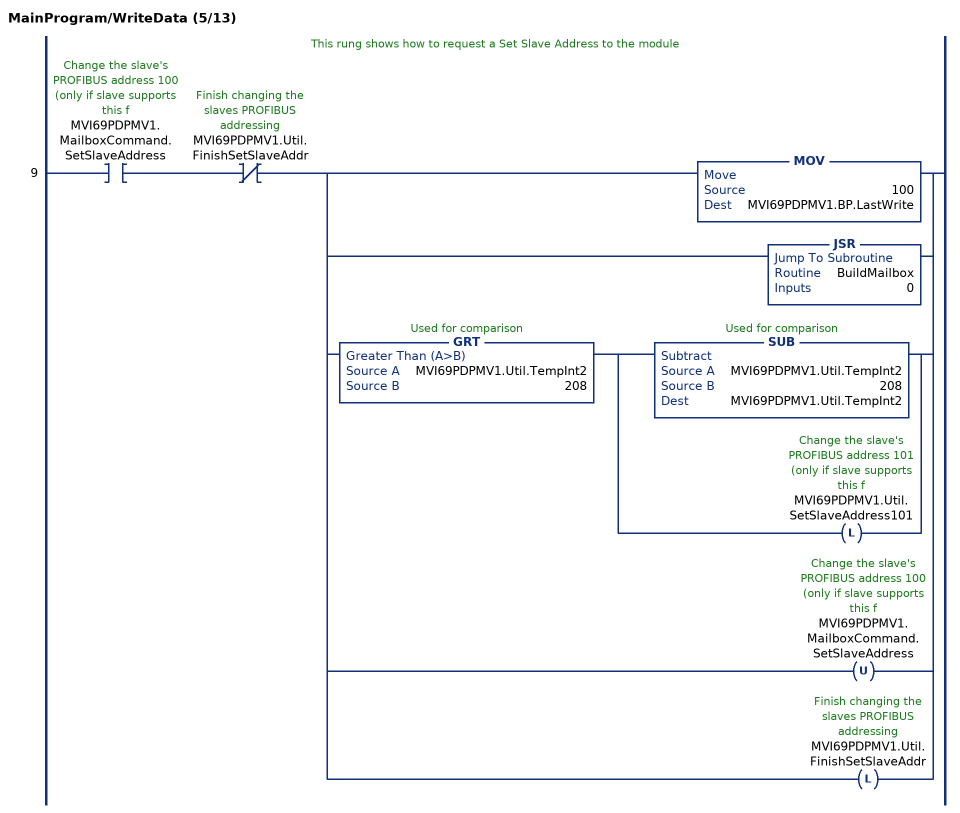
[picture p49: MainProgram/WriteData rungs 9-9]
   // This rung shows how to request a Set Slave Address to the module
   9: XIC(MVI69PDPMV1.MailboxCommand.SetSlaveAddress)XIO(MVI69PDPMV1.Util.FinishSetSlaveAddr)[MOV(100,MVI69PDPMV1.BP.LastWrite) ,JSR(BuildMailbox,0) ,GRT(MVI69PDPMV1.Util.TempInt2,208) [SUB(MVI69PDPMV1.Util.TempInt2,208,MVI69PDPMV1.Util.TempInt2) ,OTL(MVI69PDPMV1.Util.SetSlaveAddress101) ] ,OTU(MVI69PDPMV1.MailboxCommand.SetSlaveAddress) ,OTL(MVI69PDPMV1.Util.FinishSetSlaveAddr) ];
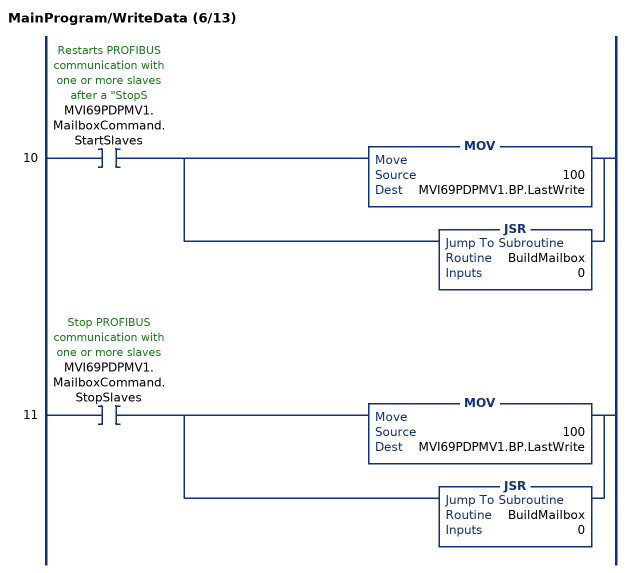
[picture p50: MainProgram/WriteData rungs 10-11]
   10: XIC(MVI69PDPMV1.MailboxCommand.StartSlaves)[MOV(100,MVI69PDPMV1.BP.LastWrite) ,JSR(BuildMailbox,0) ];
   11: XIC(MVI69PDPMV1.MailboxCommand.StopSlaves)[MOV(100,MVI69PDPMV1.BP.LastWrite) ,JSR(BuildMailbox,0) ];
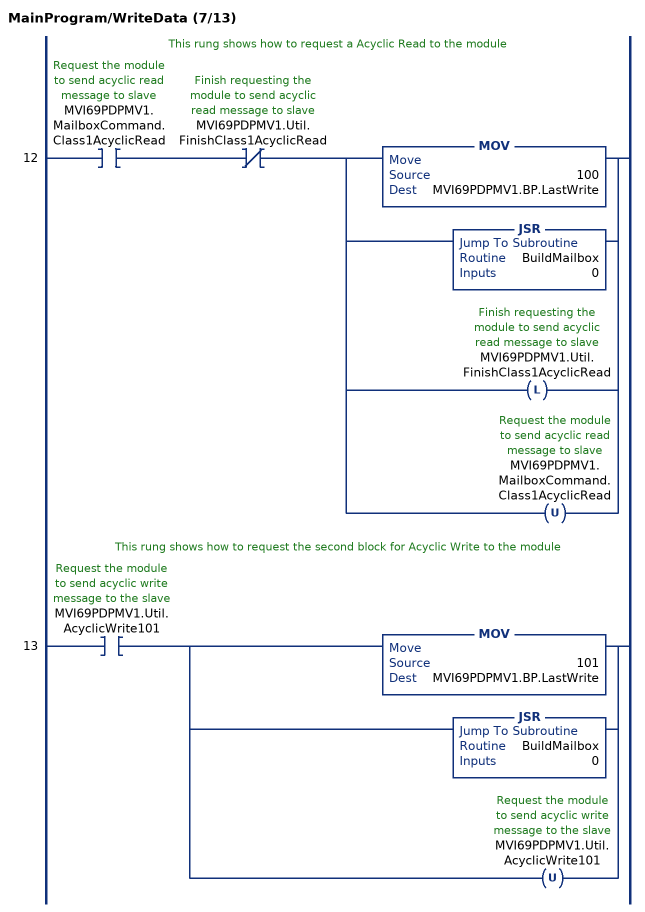
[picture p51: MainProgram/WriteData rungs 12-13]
   // This rung shows how to request a Acyclic Read to the module
   12: XIC(MVI69PDPMV1.MailboxCommand.Class1AcyclicRead)XIO(MVI69PDPMV1.Util.FinishClass1AcyclicRead)[MOV(100,MVI69PDPMV1.BP.LastWrite) ,JSR(BuildMailbox,0) ,OTL(MVI69PDPMV1.Util.FinishClass1AcyclicRead) ,OTU(MVI69PDPMV1.MailboxCommand.Class1AcyclicRead) ];
   // This rung shows how to request the second block for Acyclic Write to the module
   13: XIC(MVI69PDPMV1.Util.AcyclicWrite101)[MOV(101,MVI69PDPMV1.BP.LastWrite) ,JSR(BuildMailbox,0) ,OTU(MVI69PDPMV1.Util.AcyclicWrite101) ];
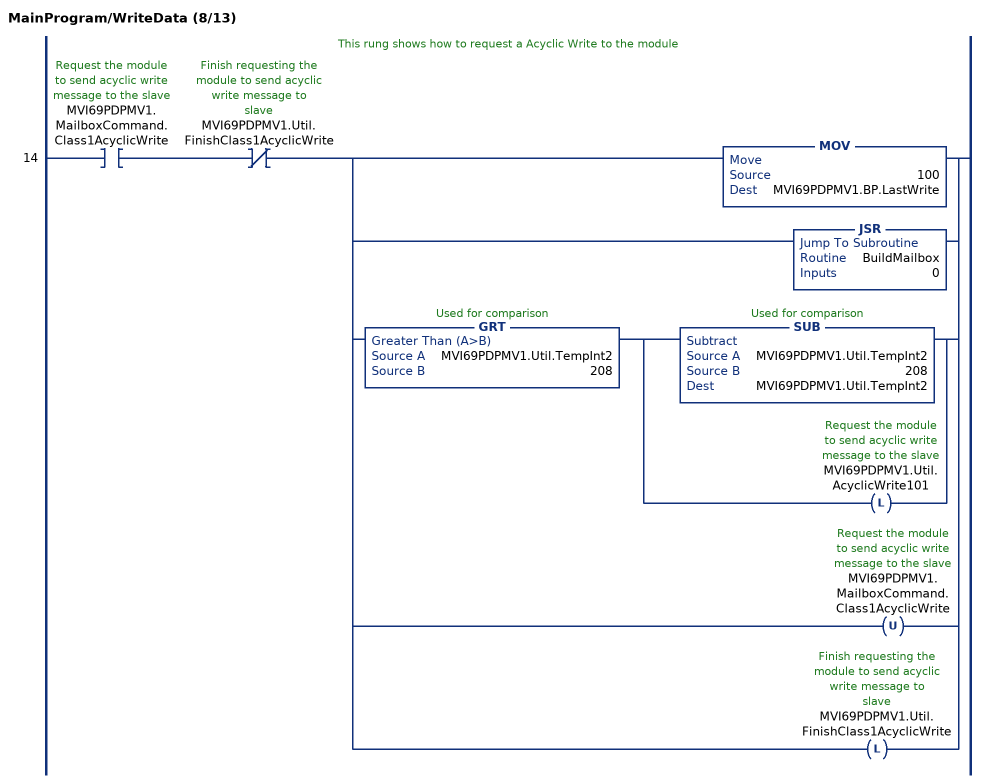
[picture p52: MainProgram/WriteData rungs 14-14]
   // This rung shows how to request a Acyclic Write to the module
   14: XIC(MVI69PDPMV1.MailboxCommand.Class1AcyclicWrite)XIO(MVI69PDPMV1.Util.FinishClass1AcyclicWrite)[MOV(100,MVI69PDPMV1.BP.LastWrite) ,JSR(BuildMailbox,0) ,GRT(MVI69PDPMV1.Util.TempInt2,208) [SUB(MVI69PDPMV1.Util.TempInt2,208,MVI69PDPMV1.Util.TempInt2) ,OTL(MVI69PDPMV1.Util.AcyclicWrite101) ] ,OTU(MVI69PDPMV1.MailboxCommand.Class1AcyclicWrite) ,OTL(MVI69PDPMV1.Util.FinishClass1AcyclicWrite) ];
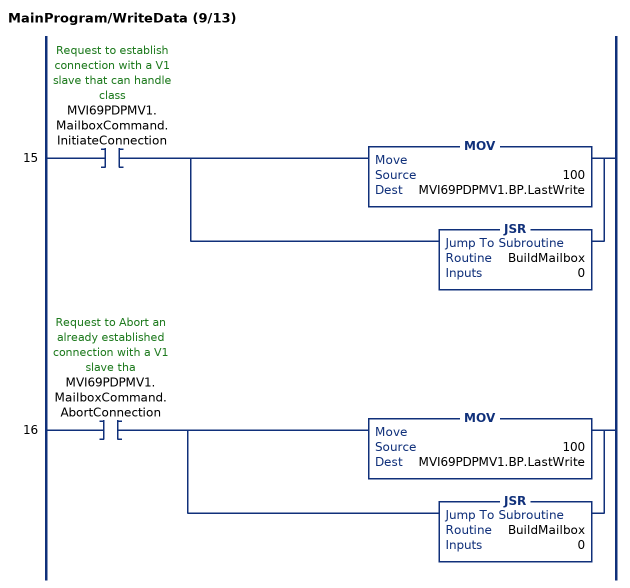
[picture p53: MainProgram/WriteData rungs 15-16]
   15: XIC(MVI69PDPMV1.MailboxCommand.InitiateConnection)[MOV(100,MVI69PDPMV1.BP.LastWrite) ,JSR(BuildMailbox,0) ];
   16: XIC(MVI69PDPMV1.MailboxCommand.AbortConnection)[MOV(100,MVI69PDPMV1.BP.LastWrite) ,JSR(BuildMailbox,0) ];
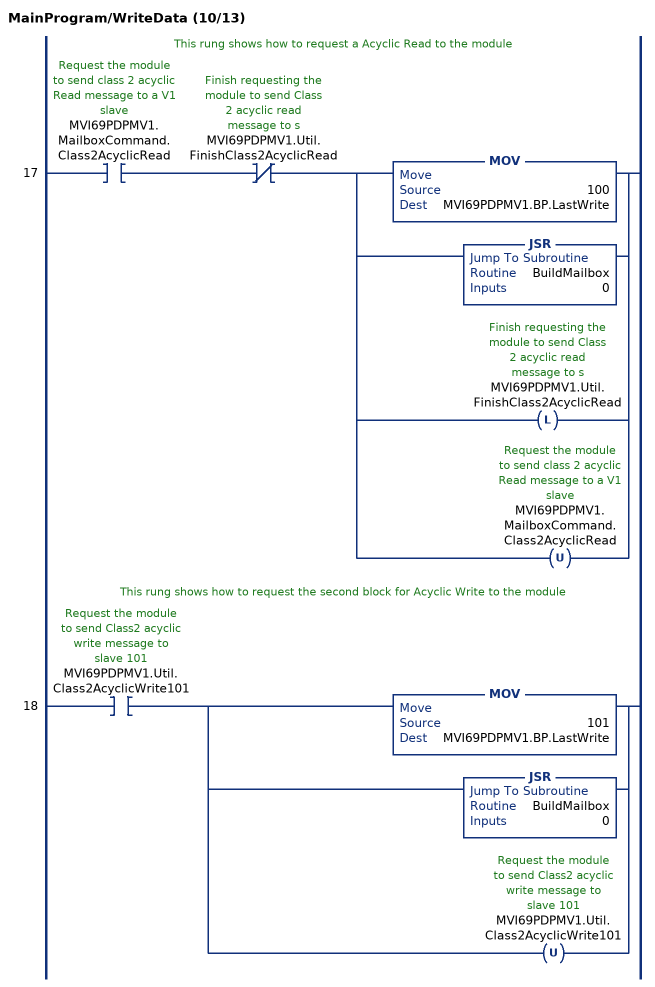
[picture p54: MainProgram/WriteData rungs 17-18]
   // This rung shows how to request a Acyclic Read to the module
   17: XIC(MVI69PDPMV1.MailboxCommand.Class2AcyclicRead)XIO(MVI69PDPMV1.Util.FinishClass2AcyclicRead)[MOV(100,MVI69PDPMV1.BP.LastWrite) ,JSR(BuildMailbox,0) ,OTL(MVI69PDPMV1.Util.FinishClass2AcyclicRead) ,OTU(MVI69PDPMV1.MailboxCommand.Class2AcyclicRead) ];
   // This rung shows how to request the second block for Acyclic Write to the module
   18: XIC(MVI69PDPMV1.Util.Class2AcyclicWrite101)[MOV(101,MVI69PDPMV1.BP.LastWrite) ,JSR(BuildMailbox,0) ,OTU(MVI69PDPMV1.Util.Class2AcyclicWrite101) ];
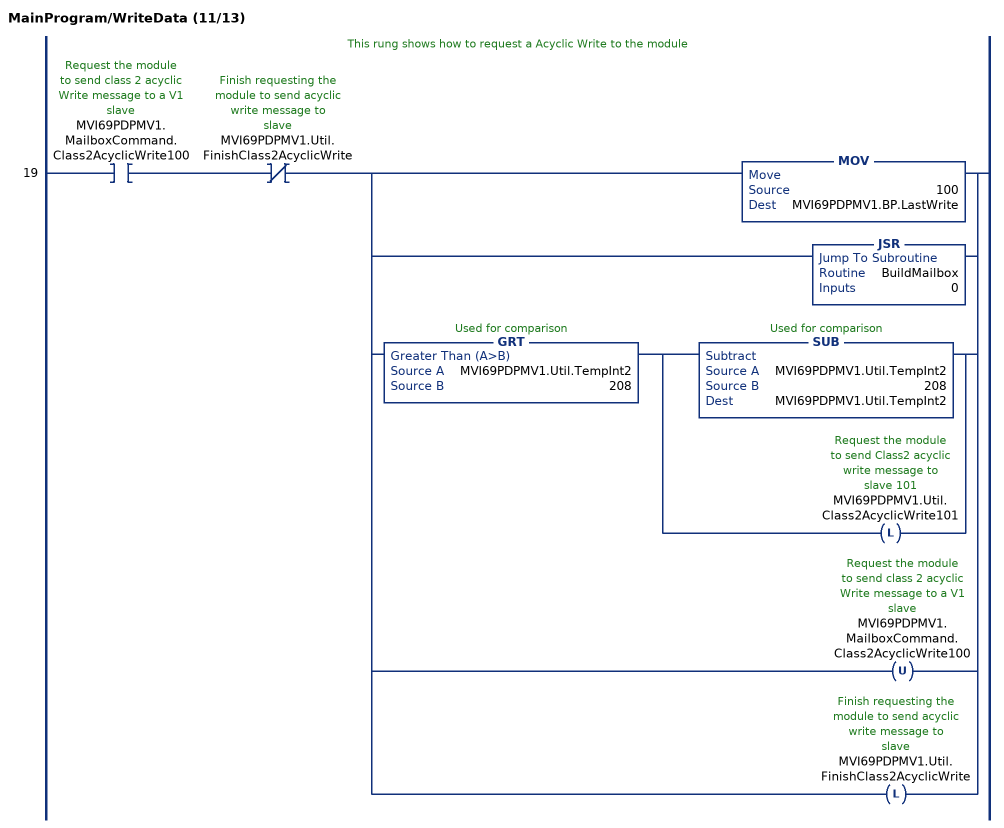
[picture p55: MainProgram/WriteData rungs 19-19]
   // This rung shows how to request a Acyclic Write to the module
   19: XIC(MVI69PDPMV1.MailboxCommand.Class2AcyclicWrite100)XIO(MVI69PDPMV1.Util.FinishClass2AcyclicWrite)[MOV(100,MVI69PDPMV1.BP.LastWrite) ,JSR(BuildMailbox,0) ,GRT(MVI69PDPMV1.Util.TempInt2,208) [SUB(MVI69PDPMV1.Util.TempInt2,208,MVI69PDPMV1.Util.TempInt2) ,OTL(MVI69PDPMV1.Util.Class2AcyclicWrite101) ] ,OTU(MVI69PDPMV1.MailboxCommand.Class2AcyclicWrite100) ,OTL(MVI69PDPMV1.Util.FinishClass2AcyclicWrite) ];
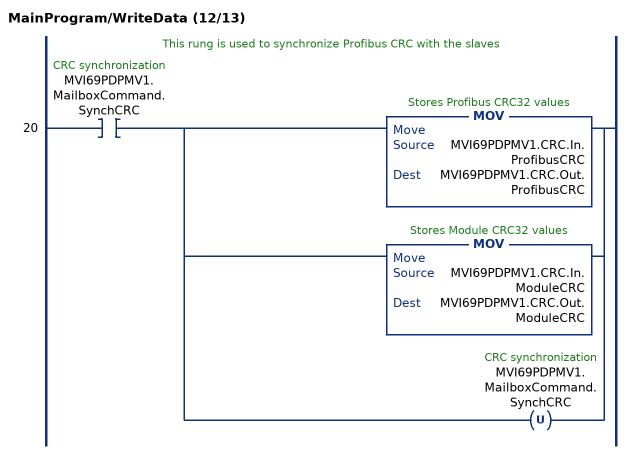
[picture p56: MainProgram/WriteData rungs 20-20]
   // This rung is used to synchronize Profibus CRC with the slaves
   20: XIC(MVI69PDPMV1.MailboxCommand.SynchCRC)[MOV(MVI69PDPMV1.CRC.In.ProfibusCRC,MVI69PDPMV1.CRC.Out.ProfibusCRC) ,MOV(MVI69PDPMV1.CRC.In.ModuleCRC,MVI69PDPMV1.CRC.Out.ModuleCRC) ,OTU(MVI69PDPMV1.MailboxCommand.SynchCRC) ];
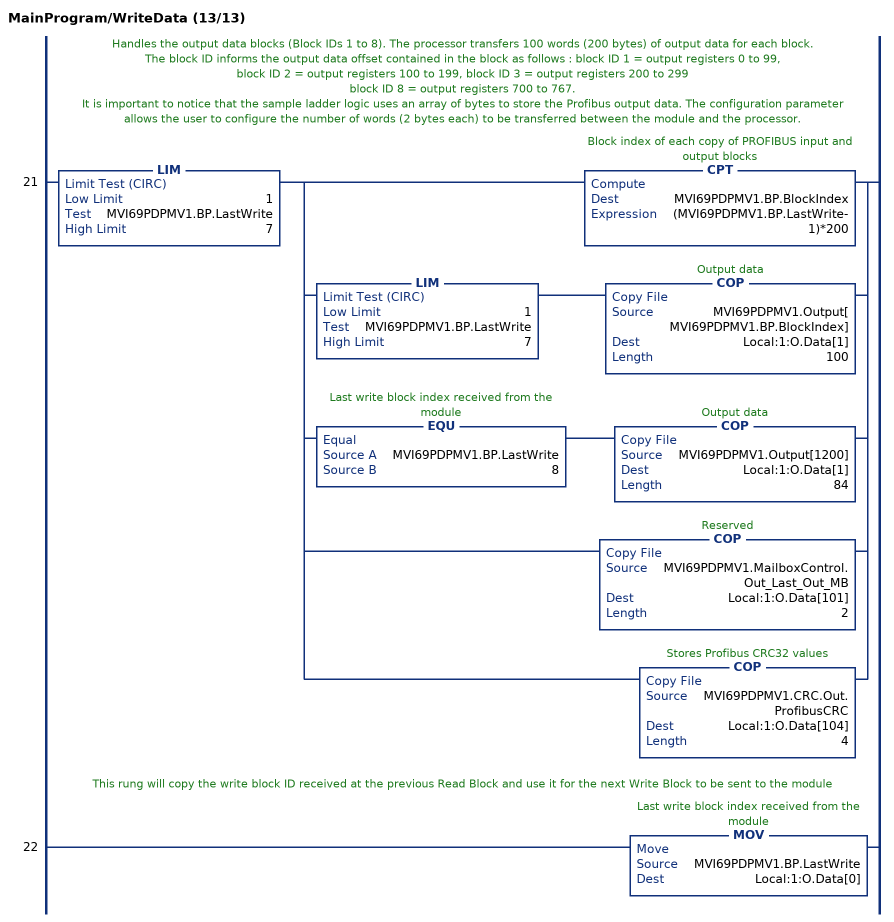
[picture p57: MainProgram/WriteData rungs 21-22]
   // Handles the output data blocks (Block IDs 1 to 8). The processor transfers 100 words (200 bytes) of output data for each block.
   // The block ID informs the output data offset contained in the block as follows : block ID 1 = output registers 0 to 99,
   // block ID 2 = output registers 100 to 199, block ID 3 = output registers 200 to 299
   //  block ID 8 = output registers 700 to 767.
   // It is important to notice that the sample ladder logic uses an array of bytes to store the Profibus output data. The configuration parameter allows the user to configure the number of words (2 bytes each) to be transferred between the module and the processor.
   21: LIM(1,MVI69PDPMV1.BP.LastWrite,7)[CPT(MVI69PDPMV1.BP.BlockIndex,(MVI69PDPMV1.BP.LastWrite-1)*200) ,LIM(1,MVI69PDPMV1.BP.LastWrite,7) COP(MVI69PDPMV1.Output[MVI69PDPMV1.BP.BlockIndex],Local:1:O.Data[1],100) ,EQU(MVI69PDPMV1.BP.LastWrite,8) COP(MVI69PDPMV1.Output[1200],Local:1:O.Data[1],84) ,COP(MVI69PDPMV1.MailboxControl.Out_Last_Out_MB,Local:1:O.Data[101],2) ,COP(MVI69PDPMV1.CRC.Out.ProfibusCRC,Local:1:O.Data[104],4) ];
   // This rung will copy the write block ID received at the previous Read Block and use it for the next Write Block to be sent to the module
   22: MOV(MVI69PDPMV1.BP.LastWrite,Local:1:O.Data[0]);
END_ROUTINE
END_PROGRAM
